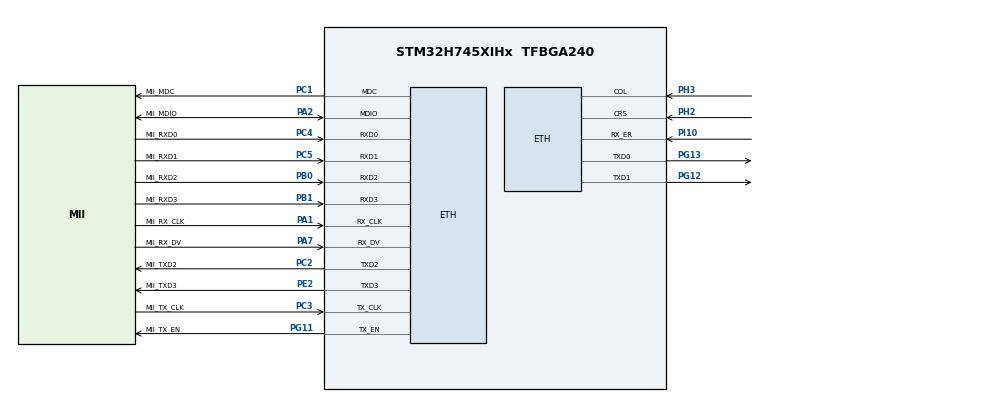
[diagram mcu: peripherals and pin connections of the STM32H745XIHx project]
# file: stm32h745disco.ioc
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CORTEX_M7.AccessPermission-Cortex_Memory_Protection_Unit_Region0_Settings=MPU_REGION_FULL_ACCESS
CORTEX_M7.BaseAddress-Cortex_Memory_Protection_Unit_Region0_Settings=0x30040000
CORTEX_M7.CPU_DCache=Enabled
CORTEX_M7.CPU_ICache=Enabled
CORTEX_M7.Enable-Cortex_Memory_Protection_Unit_Region0_Settings=MPU_REGION_ENABLE
CORTEX_M7.IsBufferable-Cortex_Memory_Protection_Unit_Region0_Settings=MPU_ACCESS_BUFFERABLE
CORTEX_M7.IsShareable-Cortex_Memory_Protection_Unit_Region0_Settings=MPU_ACCESS_SHAREABLE
CORTEX_M7.MPU_Control=MPU_PRIVILEGED_DEFAULT
CORTEX_M7.Size-Cortex_Memory_Protection_Unit_Region0_Settings=MPU_REGION_SIZE_256B
CortexM4.IPs=CORTEX_M4\:I,DEBUG,FATFS_M4\:I,FREERTOS_M4\:I,IWDG2\:I,OPENAMP_M4\:I,PDM2PCM_M4\:I,PWR,RCC,RESMGR_UTILITY,SYS_M4\:I,USB_DEVICE_M4\:I,USB_HOST_M4\:I,VREFBUF,WWDG2\:I,DMA,BDMA,MDMA,NVIC2\:I
CortexM7.IPs=CORTEX_M7\:I,DEBUG\:I,FATFS_M7\:I,FREERTOS_M7\:I,IWDG1\:I,OPENAMP_M7\:I,PDM2PCM_M7\:I,PWR\:I,RCC\:I,RESMGR_UTILITY\:I,SYS\:I,USB_DEVICE_M7\:I,USB_HOST_M7\:I,VREFBUF\:I,WWDG1\:I,DMA\:I,BDMA\:I,MDMA\:I,NVIC1\:I,ETH\:I
ETH.MediaInterface=HAL_ETH_MII_MODE
Mcu.Family=STM32H7
Mcu.Name=STM32H745XIHx
Mcu.Package=TFBGA240
NVIC1.ETH_IRQn=true\:0\:0\:false\:false\:true\:true\:true
NVIC1.PriorityGroup=NVIC_PRIORITYGROUP_4
NVIC2.PriorityGroup=NVIC_PRIORITYGROUP_4
PA1.GPIO_Label=MII_RX_CLK
PA1.Mode=MII
PA1.PinAttribute=CortexM7
PA1.Signal=ETH_RX_CLK
PA2.GPIO_Label=MII_MDIO
PA2.Mode=MII
PA2.PinAttribute=CortexM7
PA2.Signal=ETH_MDIO
PA7.GPIO_Label=MII_RX_DV
PA7.Mode=MII
PA7.PinAttribute=CortexM7
PA7.Signal=ETH_RX_DV
PB0.GPIO_Label=MII_RXD2
PB0.Mode=MII
PB0.PinAttribute=CortexM7
PB0.Signal=ETH_RXD2
PB1.GPIO_Label=MII_RXD3
PB1.Mode=MII
PB1.PinAttribute=CortexM7
PB1.Signal=ETH_RXD3
PC1.GPIO_Label=MII_MDC
PC1.Mode=MII
PC1.PinAttribute=CortexM7
PC1.Signal=ETH_MDC
PC2.GPIO_Label=MII_TXD2
PC2.Mode=MII
PC2.PinAttribute=CortexM7
PC2.Signal=ETH_TXD2
PC3.GPIO_Label=MII_TX_CLK
PC3.Mode=MII
PC3.PinAttribute=CortexM7
PC3.Signal=ETH_TX_CLK
PC4.GPIO_Label=MII_RXD0
PC4.Mode=MII
PC4.PinAttribute=CortexM7
PC4.Signal=ETH_RXD0
PC5.GPIO_Label=MII_RXD1
PC5.Mode=MII
PC5.PinAttribute=CortexM7
PC5.Signal=ETH_RXD1
PE2.GPIO_Label=MII_TXD3
PE2.Mode=MII
PE2.PinAttribute=CortexM7
PE2.Signal=ETH_TXD3
PG11.GPIO_Label=MII_TX_EN
PG11.Mode=MII
PG11.PinAttribute=CortexM7
PG11.Signal=ETH_TX_EN
PG12.Mode=MII
PG12.PinAttribute=CortexM7
PG12.Signal=ETH_TXD1
PG13.Mode=MII
PG13.PinAttribute=CortexM7
PG13.Signal=ETH_TXD0
PH0-OSC_IN\ (PH0).Mode=HSE-External-Oscillator
PH0-OSC_IN\ (PH0).PinAttribute=CortexM7
PH0-OSC_IN\ (PH0).Signal=RCC_OSC_IN
PH1-OSC_OUT\ (PH1).Mode=HSE-External-Oscillator
PH1-OSC_OUT\ (PH1).PinAttribute=CortexM7
PH1-OSC_OUT\ (PH1).Signal=RCC_OSC_OUT
PH2.Mode=MII
PH2.PinAttribute=CortexM7
PH2.Signal=ETH_CRS
PH3.Mode=MII
PH3.PinAttribute=CortexM7
PH3.Signal=ETH_COL
PI10.Mode=Activate Rx Err signal
PI10.PinAttribute=CortexM7
PI10.Signal=ETH_RX_ER
ProjectManager.HeapSize=M4-0x200,M7-0x200
ProjectManager.StackSize=M4-0x400,M7-0x400
ProjectManager.TargetToolchain=MDK-ARM V5
RCC.ADCFreq_Value=50390625
RCC.APB1Freq_Value=100000000
RCC.APB2Freq_Value=100000000
RCC.APB3Freq_Value=100000000
RCC.APB4Freq_Value=100000000
RCC.CortexFreq_Value=400000000
RCC.D1PPRE=RCC_APB3_DIV2
RCC.D2PPRE1=RCC_APB1_DIV2
RCC.D2PPRE2=RCC_APB2_DIV2
RCC.D3PPRE=RCC_APB4_DIV2
RCC.DIVM1=2
RCC.DIVN1=64
RCC.HCLKFreq_Value=200000000
RCC.HPRE=RCC_HCLK_DIV2
RCC.PLLFRACN=0
RCC.PLLSourceVirtual=RCC_PLLSOURCE_HSE
RCC.SYSCLKFreq_VALUE=400000000
RCC.SYSCLKSource=RCC_SYSCLKSOURCE_PLLCLK
RCC.SupplySource=PWR_DIRECT_SMPS_SUPPLY
RCC.USBFreq_Value=400000000
VP_SYS_M4_VS_Systick.Mode=SysTick
board=custom

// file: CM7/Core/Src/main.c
/* USER CODE BEGIN Header */
/**
  ******************************************************************************
  * @file           : main.c
  * @brief          : Main program body
  ******************************************************************************
  * @attention
  *
  * <h2><center>&copy; Copyright (c) 2020 STMicroelectronics.
  * All rights reserved.</center></h2>
  *
  * This software component is licensed by ST under BSD 3-Clause license,
  * the "License"; You may not use this file except in compliance with the
  * License. You may obtain a copy of the License at:
  *                        opensource.org/licenses/BSD-3-Clause
  *
  ******************************************************************************
  */
/* USER CODE END Header */
#include "main.h"
#include "gpio.h"

/* USER CODE BEGIN PD */

#define HSEM_ID_0 (0U) /* HW semaphore 0*/
/* USER CODE END PD */

void SystemClock_Config(void);

int main(void)
{

/* USER CODE BEGIN Boot_Mode_Sequence_0 */
  int32_t timeout;
/* USER CODE END Boot_Mode_Sequence_0 */

/* USER CODE BEGIN Boot_Mode_Sequence_1 */
  /* Wait until CPU2 boots and enters in stop mode or timeout*/
  timeout = 0xFFFF;
  while((__HAL_RCC_GET_FLAG(RCC_FLAG_D2CKRDY) != RESET) && (timeout-- > 0));
  if ( timeout < 0 )
  {
  Error_Handler();
  }
/* USER CODE END Boot_Mode_Sequence_1 */
  /* MCU Configuration--------------------------------------------------------*/

  /* Reset of all peripherals, Initializes the Flash interface and the Systick. */
  HAL_Init();

  /* Configure the system clock */
  SystemClock_Config();
/* USER CODE BEGIN Boot_Mode_Sequence_2 */
/* When system initialization is finished, Cortex-M7 will release Cortex-M4 by means of
HSEM notification */
/*HW semaphore Clock enable*/
__HAL_RCC_HSEM_CLK_ENABLE();
/*Take HSEM */
HAL_HSEM_FastTake(HSEM_ID_0);
/*Release HSEM in order to notify the CPU2(CM4)*/
HAL_HSEM_Release(HSEM_ID_0,0);
/* wait until CPU2 wakes up from stop mode */
timeout = 0xFFFF;
while((__HAL_RCC_GET_FLAG(RCC_FLAG_D2CKRDY) == RESET) && (timeout-- > 0));
if ( timeout < 0 )
{
Error_Handler();
}
/* USER CODE END Boot_Mode_Sequence_2 */

  /* Initialize all configured peripherals */
  MX_GPIO_Init();

  /* Infinite loop */
  while (1)
  {

  }
}

void SystemClock_Config(void)
{
  RCC_OscInitTypeDef RCC_OscInitStruct = {0};
  RCC_ClkInitTypeDef RCC_ClkInitStruct = {0};
  RCC_PeriphCLKInitTypeDef PeriphClkInitStruct = {0};

  /** Supply configuration update enable
  */
  HAL_PWREx_ConfigSupply(PWR_DIRECT_SMPS_SUPPLY);
  /** Configure the main internal regulator output voltage
  */
  __HAL_PWR_VOLTAGESCALING_CONFIG(PWR_REGULATOR_VOLTAGE_SCALE3);

  while(!__HAL_PWR_GET_FLAG(PWR_FLAG_VOSRDY)) {}
  /** Macro to configure the PLL clock source
  */
  __HAL_RCC_PLL_PLLSOURCE_CONFIG(RCC_PLLSOURCE_HSE);
  /** Initializes the RCC Oscillators according to the specified parameters
  * in the RCC_OscInitTypeDef structure.
  */
  RCC_OscInitStruct.OscillatorType = RCC_OSCILLATORTYPE_HSI|RCC_OSCILLATORTYPE_HSE;
  RCC_OscInitStruct.HSEState = RCC_HSE_BYPASS;
  RCC_OscInitStruct.HSIState = RCC_HSI_DIV1;
  RCC_OscInitStruct.HSICalibrationValue = RCC_HSICALIBRATION_DEFAULT;
  RCC_OscInitStruct.PLL.PLLState = RCC_PLL_ON;
  RCC_OscInitStruct.PLL.PLLSource = RCC_PLLSOURCE_HSE;
  RCC_OscInitStruct.PLL.PLLM = 23;
  RCC_OscInitStruct.PLL.PLLN = 177;
  RCC_OscInitStruct.PLL.PLLP = 2;
  RCC_OscInitStruct.PLL.PLLQ = 4;
  RCC_OscInitStruct.PLL.PLLR = 4;
  RCC_OscInitStruct.PLL.PLLRGE = RCC_PLL1VCIRANGE_0;
  RCC_OscInitStruct.PLL.PLLVCOSEL = RCC_PLL1VCOWIDE;
  RCC_OscInitStruct.PLL.PLLFRACN = 0;
  if (HAL_RCC_OscConfig(&RCC_OscInitStruct) != HAL_OK)
  {
    Error_Handler();
  }
  /** Initializes the CPU, AHB and APB buses clocks
  */
  RCC_ClkInitStruct.ClockType = RCC_CLOCKTYPE_HCLK|RCC_CLOCKTYPE_SYSCLK
                              |RCC_CLOCKTYPE_PCLK1|RCC_CLOCKTYPE_PCLK2
                              |RCC_CLOCKTYPE_D3PCLK1|RCC_CLOCKTYPE_D1PCLK1;
  RCC_ClkInitStruct.SYSCLKSource = RCC_SYSCLKSOURCE_HSI;
  RCC_ClkInitStruct.SYSCLKDivider = RCC_SYSCLK_DIV1;
  RCC_ClkInitStruct.AHBCLKDivider = RCC_HCLK_DIV1;
  RCC_ClkInitStruct.APB3CLKDivider = RCC_APB3_DIV1;
  RCC_ClkInitStruct.APB1CLKDivider = RCC_APB1_DIV1;
  RCC_ClkInitStruct.APB2CLKDivider = RCC_APB2_DIV1;
  RCC_ClkInitStruct.APB4CLKDivider = RCC_APB4_DIV1;

  if (HAL_RCC_ClockConfig(&RCC_ClkInitStruct, FLASH_LATENCY_0) != HAL_OK)
  {
    Error_Handler();
  }
  PeriphClkInitStruct.PeriphClockSelection = RCC_PERIPHCLK_LTDC|RCC_PERIPHCLK_USART3
                              |RCC_PERIPHCLK_FDCAN|RCC_PERIPHCLK_SAI2
                              |RCC_PERIPHCLK_SDMMC|RCC_PERIPHCLK_USB
                              |RCC_PERIPHCLK_QSPI|RCC_PERIPHCLK_FMC;
  PeriphClkInitStruct.PLL3.PLL3M = 32;
  PeriphClkInitStruct.PLL3.PLL3N = 129;
  PeriphClkInitStruct.PLL3.PLL3P = 2;
  PeriphClkInitStruct.PLL3.PLL3Q = 2;
  PeriphClkInitStruct.PLL3.PLL3R = 2;
  PeriphClkInitStruct.PLL3.PLL3RGE = RCC_PLL3VCIRANGE_3;
  PeriphClkInitStruct.PLL3.PLL3VCOSEL = RCC_PLL3VCOWIDE;
  PeriphClkInitStruct.PLL3.PLL3FRACN = 0;
  PeriphClkInitStruct.FmcClockSelection = RCC_FMCCLKSOURCE_D1HCLK;
  PeriphClkInitStruct.QspiClockSelection = RCC_QSPICLKSOURCE_D1HCLK;
  PeriphClkInitStruct.SdmmcClockSelection = RCC_SDMMCCLKSOURCE_PLL;
  PeriphClkInitStruct.Sai23ClockSelection = RCC_SAI23CLKSOURCE_PLL;
  PeriphClkInitStruct.FdcanClockSelection = RCC_FDCANCLKSOURCE_PLL;
  PeriphClkInitStruct.Usart234578ClockSelection = RCC_USART234578CLKSOURCE_D2PCLK1;
  PeriphClkInitStruct.UsbClockSelection = RCC_USBCLKSOURCE_PLL;
  if (HAL_RCCEx_PeriphCLKConfig(&PeriphClkInitStruct) != HAL_OK)
  {
    Error_Handler();
  }
  /** Enable USB Voltage detector
  */
  HAL_PWREx_EnableUSBVoltageDetector();
}

void Error_Handler(void)
{
}

/************************ (C) COPYRIGHT STMicroelectronics *****END OF FILE****/
